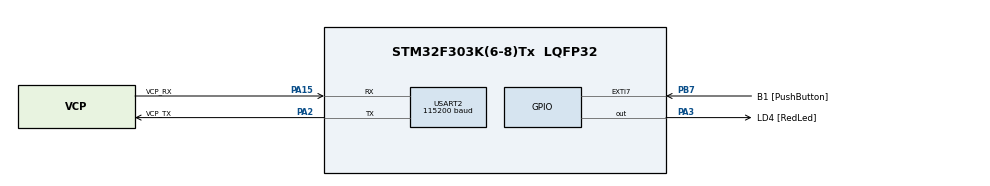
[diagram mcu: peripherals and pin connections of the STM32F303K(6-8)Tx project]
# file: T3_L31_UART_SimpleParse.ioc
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Mcu.Family=STM32F3
Mcu.Name=STM32F303K(6-8)Tx
Mcu.Package=LQFP32
NVIC.PriorityGroup=NVIC_PRIORITYGROUP_4
NVIC.USART2_IRQn=true\:0\:0\:false\:true\:true\:1\:true\:true
PA13.GPIO_Label=SWDIO
PA13.Mode=Serial_Wire
PA13.Signal=SYS_JTMS-SWDIO
PA14.GPIO_Label=SWCLK
PA14.Mode=Serial_Wire
PA14.Signal=SYS_JTCK-SWCLK
PA15.GPIO_Label=VCP_RX
PA15.Mode=Asynchronous
PA15.Signal=USART2_RX
PA2.GPIO_Label=VCP_TX
PA2.Mode=Asynchronous
PA2.Signal=USART2_TX
PA3.GPIO_Label=LD4 [RedLed]
PA3.Signal=GPIO_Output
PB7.GPIO_Label=B1 [PushButton]
PB7.Signal=GPXTI7
PF0\ /\ OSC_IN.GPIO_Label=MCO
PF0\ /\ OSC_IN.Mode=HSE-External-Clock-Source
PF0\ /\ OSC_IN.Signal=RCC_OSC_IN
ProjectManager.HeapSize=0x200
ProjectManager.StackSize=0x400
ProjectManager.TargetToolchain=STM32CubeIDE
RCC.AHBFreq_Value=8000000
RCC.APB1Freq_Value=8000000
RCC.APB2Freq_Value=8000000
RCC.CortexFreq_Value=8000000
RCC.HSE_VALUE=8000000
RCC.HSI_VALUE=8000000
RCC.SYSCLKFreq_VALUE=8000000
USART2.BaudRate=115200
USART2.VirtualMode-Asynchronous=VM_ASYNC
board=NUCLEO-F303K8

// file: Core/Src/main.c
/* USER CODE BEGIN Header */
/**
  ******************************************************************************
  * @file           : main.c
  * @brief          : Main program body
  ******************************************************************************
  * @attention
  *
  * Copyright (c) 2022 STMicroelectronics.
  * All rights reserved.
  *
  * This software is licensed under terms that can be found in the LICENSE file
  * in the root directory of this software component.
  * If no LICENSE file comes with this software, it is provided AS-IS.
  *
  ******************************************************************************
  */
/* USER CODE END Header */
#include "main.h"
#include "usart.h"
#include "gpio.h"

/* USER CODE BEGIN Includes */
#include "ring_buffer.h"
#include "string.h"
#include "parser_simple.h"
/* USER CODE END Includes */

/* USER CODE BEGIN PV */
RingBuffer_t ReceiveBuffer;
uint8_t ReceiveTmp;
uint8_t ReceivedLines;

uint8_t ReceivedData[32];
/* USER CODE END PV */

void SystemClock_Config(void);
static void MX_NVIC_Init(void);

int main(void)
{

  /* MCU Configuration--------------------------------------------------------*/

  /* Reset of all peripherals, Initializes the Flash interface and the Systick. */
  HAL_Init();

  /* Configure the system clock */
  SystemClock_Config();

  /* Initialize all configured peripherals */
  MX_GPIO_Init();
  MX_USART2_UART_Init();

  /* Initialize interrupts */
  MX_NVIC_Init();
  /* USER CODE BEGIN 2 */
  HAL_UART_Receive_IT(&huart2, &ReceiveTmp, 1);

  /* USER CODE END 2 */

  /* Infinite loop */
  /* USER CODE BEGIN WHILE */
  while (1)
  {
	  if(ReceivedLines > 0)
	  {

		  Parser_TakeLine(&ReceiveBuffer, ReceivedData);
		  ReceivedLines--;

		  Parser_Parse(ReceivedData);

	  }
    /* USER CODE END WHILE */

  }
}

void SystemClock_Config(void)
{
  RCC_OscInitTypeDef RCC_OscInitStruct = {0};
  RCC_ClkInitTypeDef RCC_ClkInitStruct = {0};

  /** Configure the main internal regulator output voltage
  */
  __HAL_RCC_PWR_CLK_ENABLE();
  __HAL_PWR_VOLTAGESCALING_CONFIG(PWR_REGULATOR_VOLTAGE_SCALE1);
  /** Initializes the RCC Oscillators according to the specified parameters
  * in the RCC_OscInitTypeDef structure.
  */
  RCC_OscInitStruct.OscillatorType = RCC_OSCILLATORTYPE_HSI;
  RCC_OscInitStruct.HSIState = RCC_HSI_ON;
  RCC_OscInitStruct.HSICalibrationValue = RCC_HSICALIBRATION_DEFAULT;
  RCC_OscInitStruct.PLL.PLLState = RCC_PLL_ON;
  RCC_OscInitStruct.PLL.PLLSource = RCC_PLLSOURCE_HSI;
  RCC_OscInitStruct.PLL.PLLM = 16;
  RCC_OscInitStruct.PLL.PLLN = 336;
  RCC_OscInitStruct.PLL.PLLP = RCC_PLLP_DIV4;
  RCC_OscInitStruct.PLL.PLLQ = 4;
  if (HAL_RCC_OscConfig(&RCC_OscInitStruct) != HAL_OK)
  {
    Error_Handler();
  }
  /** Initializes the CPU, AHB and APB buses clocks
  */
  RCC_ClkInitStruct.ClockType = RCC_CLOCKTYPE_HCLK|RCC_CLOCKTYPE_SYSCLK
                              |RCC_CLOCKTYPE_PCLK1|RCC_CLOCKTYPE_PCLK2;
  RCC_ClkInitStruct.SYSCLKSource = RCC_SYSCLKSOURCE_PLLCLK;
  RCC_ClkInitStruct.AHBCLKDivider = RCC_SYSCLK_DIV1;
  RCC_ClkInitStruct.APB1CLKDivider = RCC_HCLK_DIV2;
  RCC_ClkInitStruct.APB2CLKDivider = RCC_HCLK_DIV1;

  if (HAL_RCC_ClockConfig(&RCC_ClkInitStruct, FLASH_LATENCY_2) != HAL_OK)
  {
    Error_Handler();
  }
}

/**
  * @brief NVIC Configuration.
  * @retval None
  */
static void MX_NVIC_Init(void)
{
  /* USART2_IRQn interrupt configuration */
  HAL_NVIC_SetPriority(USART2_IRQn, 0, 0);
  HAL_NVIC_EnableIRQ(USART2_IRQn);
}

/* USER CODE BEGIN 4 */
void HAL_UART_RxCpltCallback(UART_HandleTypeDef *huart)
{
	if(huart->Instance == USART2)
	{
		if(RB_OK == RB_Write(&ReceiveBuffer, ReceiveTmp))
		{
			if(ReceiveTmp == ENDLINE)
			{
				ReceivedLines++;
			}
		}
		HAL_UART_Receive_IT(&huart2, &ReceiveTmp, 1);
	}
}

/* USER CODE END 4 */

void Error_Handler(void)
{
  __disable_irq();
  while (1)
  {
  }
}
